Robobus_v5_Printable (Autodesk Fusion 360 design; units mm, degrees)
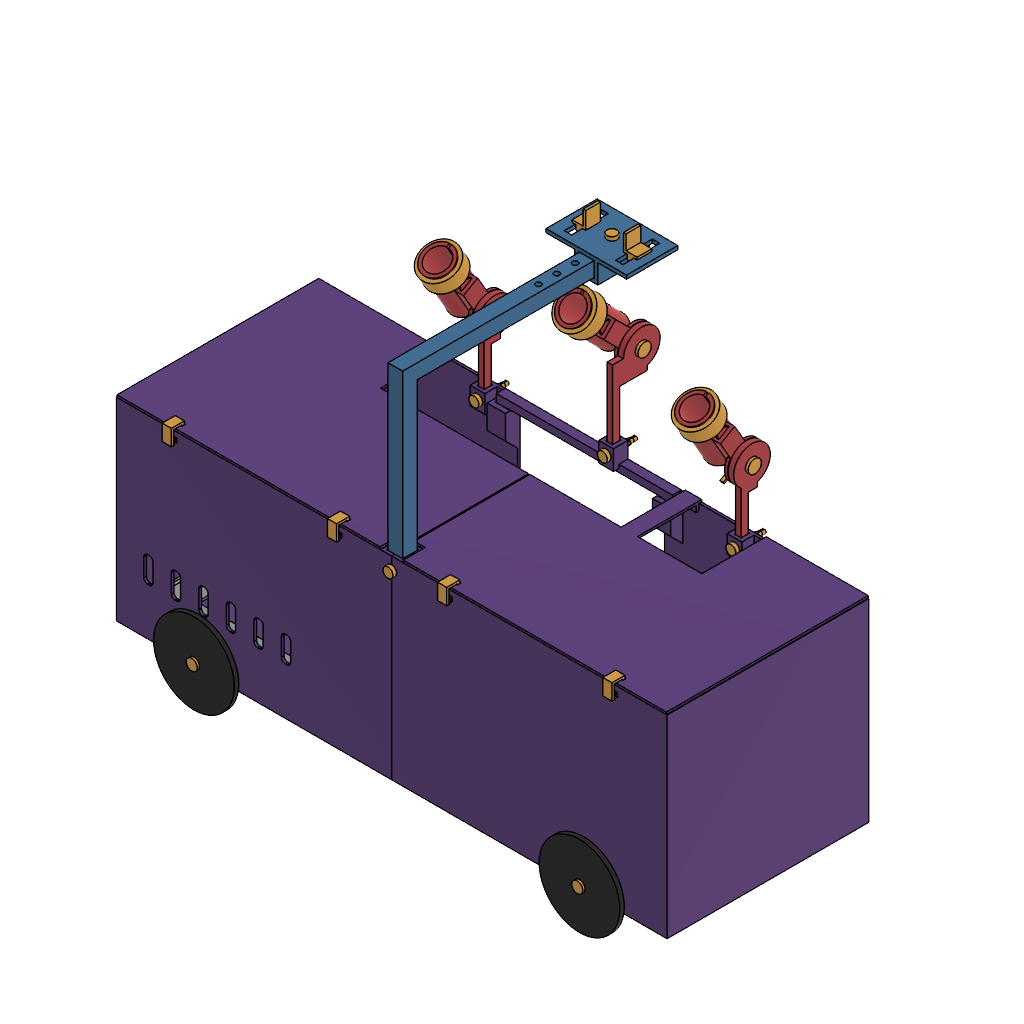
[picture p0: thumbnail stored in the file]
part number: 2026-09-26-01-44-12-449
part number: 2026-09-26-01-44-13-008
part number: 2026-09-26-01-44-13-132
part number: 2026-09-26-01-44-13-285
part number: 2026-09-26-01-44-13-384
part number: 2026-09-26-01-44-13-457
part number: 2026-09-26-01-44-13-549
part number: 2026-09-26-01-44-13-648
part number: 2026-09-26-01-44-13-727
part number: 2026-09-26-01-44-13-830
part number: 2026-09-26-01-44-14-008
part number: 2026-09-26-01-44-14-155
part number: 2026-09-26-01-44-14-251
part number: 2026-09-26-01-44-14-383
part number: 2026-09-26-01-44-14-481
part number: 2026-09-26-01-44-14-577
part number: 2026-09-26-01-44-14-681
part number: 2026-09-26-01-44-14-813
part number: 2026-09-26-01-44-14-940
part number: 2026-09-26-01-44-15-062
parameter "bodyLength" = 300 comment "Benchmark for native editable base-feature assembly; rebuild via RobobusLite.py"
parameter "bodyWidth" = 110 comment "Benchmark for native editable base-feature assembly; rebuild via RobobusLite.py"
parameter "bodyHeight" = 125 comment "Benchmark for native editable base-feature assembly; rebuild via RobobusLite.py"
parameter "wall" = 1.4 comment "Benchmark for native editable base-feature assembly; rebuild via RobobusLite.py"
parameter "floorThickness" = 1.8 comment "Benchmark for native editable base-feature assembly; rebuild via RobobusLite.py"
parameter "roofThickness" = 1.2 comment "Benchmark for native editable base-feature assembly; rebuild via RobobusLite.py"
parameter "clearance" = 0.3 comment "Benchmark for native editable base-feature assembly; rebuild via RobobusLite.py"
parameter "doorWidth" = 80 comment "Benchmark for native editable base-feature assembly; rebuild via RobobusLite.py"
parameter "doorHeight" = 100 comment "Benchmark for native editable base-feature assembly; rebuild via RobobusLite.py"
base_feature "Base Feature1" bodies "01_body_rear"
base_feature "Base Feature1" bodies "03_roof_rear"
base_feature "Base Feature1" bodies "02_body_front"
base_feature "Base Feature1" bodies "04_roof_front"
base_feature "Base Feature1" bodies "05_join_key"
copy_paste "CopyPaste1"
copy_paste "CopyPaste2"
base_feature "Base Feature1" bodies "06_roof_clip"
copy_paste "CopyPaste3"
copy_paste "CopyPaste4"
copy_paste "CopyPaste5"
base_feature "Base Feature1" bodies "07_fixed_sensor_header"
base_feature "Base Feature1" bodies "08_static_wheel"
copy_paste "CopyPaste6"
copy_paste "CopyPaste7"
copy_paste "CopyPaste8"
base_feature "Base Feature1" bodies "09_wheel_pin"
copy_paste "CopyPaste9"
copy_paste "CopyPaste10"
copy_paste "CopyPaste11"
base_feature "Base Feature1" bodies "10_breadboard_tray"
base_feature "Base Feature1" bodies "11_controller_tray"
base_feature "Base Feature1" bodies "12_tray_retainer"
copy_paste "CopyPaste12"
copy_paste "CopyPaste13"
copy_paste "CopyPaste14"
copy_paste "CopyPaste15"
copy_paste "CopyPaste16"
copy_paste "CopyPaste17"
copy_paste "CopyPaste18"
base_feature "Base Feature1" bodies "15_L1_yoke"
base_feature "Base Feature1" bodies "16_L2_yoke"
base_feature "Base Feature1" bodies "17_L3_yoke"
base_feature "Base Feature1" bodies "13_laser_pivot_adapter"
copy_paste "CopyPaste19"
copy_paste "CopyPaste20"
base_feature "Base Feature1" bodies "18_laser_carrier"
copy_paste "CopyPaste21"
copy_paste "CopyPaste22"
base_feature "Base Feature1" bodies "19_laser_collar"
copy_paste "CopyPaste23"
copy_paste "CopyPaste24"
base_feature "Base Feature1" bodies "20_pivot_pin"
copy_paste "CopyPaste25"
copy_paste "CopyPaste26"
base_feature "Base Feature1" bodies "21_pivot_wedge"
copy_paste "CopyPaste27"
copy_paste "CopyPaste28"
base_feature "Base Feature1" bodies "22_mount_pin"
copy_paste "CopyPaste29"
copy_paste "CopyPaste30"
copy_paste "CopyPaste31"
base_feature "Base Feature1" bodies "23_camera_mast_rail"
base_feature "Base Feature1" bodies "24_camera_platform"
base_feature "Base Feature1" bodies "25_camera_jaw"
copy_paste "CopyPaste32"
base_feature "Base Feature1" bodies "26_camera_index_pin"
base_feature "Base Feature1" bodies "27_ToF_bar"
base_feature "Base Feature1" bodies "28_ToF_cap"
base_feature "Base Feature1" bodies "29_ToF_jamb_clip"
copy_paste "CopyPaste33"
base_feature "Base Feature1" bodies "C01_key_0p2"
base_feature "Base Feature1" bodies "C01_key_0p3"
base_feature "Base Feature1" bodies "C01_key_0p4"
base_feature "Base Feature1" bodies "C02_bore_12"
base_feature "Base Feature1" bodies "C02_bore_12p2"
base_feature "Base Feature1" bodies "C02_bore_12p4"
base_feature "Base Feature1" bodies "C02_bore_12p6"
base_feature "Base Feature1" bodies "C02_bore_12p8"
base_feature "Base Feature1" bodies "C03_pivot_fit"
base_feature "Base Feature1" bodies "C04_angle_gauge"
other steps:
create_component "CreateComponent1"
create_component "CreateComponent2"
create_component "CreateComponent3"
create_component "CreateComponent4"
create_component "CreateComponent5"
create_component "CreateComponent6"
create_component "CreateComponent7"
create_component "CreateComponent8"
create_component "CreateComponent9"
create_component "CreateComponent10"
create_component "CreateComponent11"
create_component "CreateComponent12"
create_component "CreateComponent13"
create_component "CreateComponent14"
create_component "CreateComponent15"
create_component "CreateComponent16"
create_component "CreateComponent17"
create_component "CreateComponent18"
create_component "CreateComponent19"
create_component "CreateComponent20"
create_component "CreateComponent21"
create_component "CreateComponent22"
create_component "CreateComponent23"
create_component "CreateComponent24"
create_component "CreateComponent25"
create_component "CreateComponent26"
create_component "CreateComponent27"
create_component "CreateComponent28"
create_component "CreateComponent29"
create_component "CreateComponent30"
create_component "CreateComponent31"
create_component "CreateComponent32"
create_component "CreateComponent33"
create_component "CreateComponent34"
create_component "CreateComponent35"
create_component "CreateComponent36"
create_component "CreateComponent37"
create_component "CreateComponent38"
named bodies: "01_body_rear", "03_roof_rear", "02_body_front", "04_roof_front", "05_join_key", "06_roof_clip", "07_fixed_sensor_header", "08_static_wheel", "09_wheel_pin", "10_breadboard_tray", "11_controller_tray", "12_tray_retainer", "15_L1_yoke", "16_L2_yoke", "17_L3_yoke", "13_laser_pivot_adapter", "18_laser_carrier", "19_laser_collar", "20_pivot_pin", "21_pivot_wedge", "22_mount_pin", "23_camera_mast_rail", "24_camera_platform", "25_camera_jaw", "26_camera_index_pin", "27_ToF_bar", "28_ToF_cap", "29_ToF_jamb_clip", "C01_key_0p2", "C01_key_0p3", "C01_key_0p4", "C02_bore_12", "C02_bore_12p2", "C02_bore_12p4", "C02_bore_12p6", "C02_bore_12p8", "C03_pivot_fit", "C04_angle_gauge"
